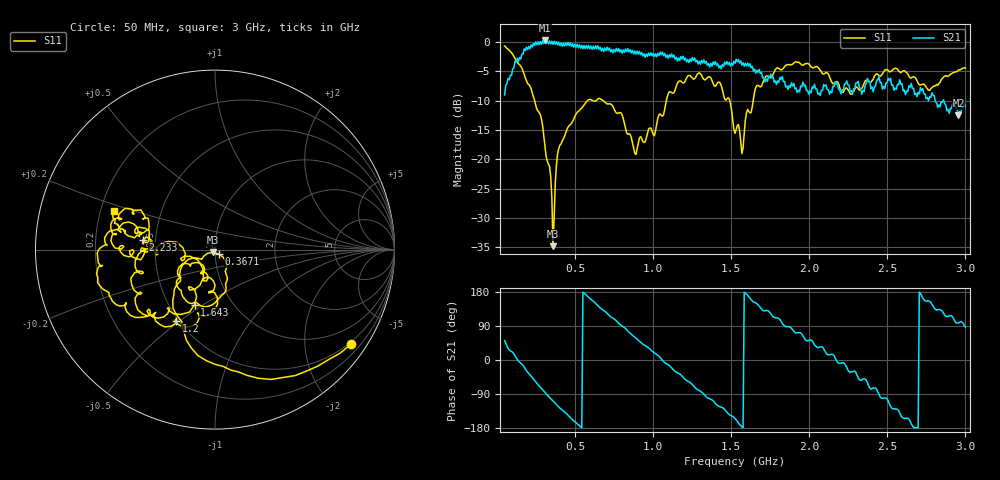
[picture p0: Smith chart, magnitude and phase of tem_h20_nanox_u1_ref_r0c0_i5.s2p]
! nanovna_capture.py 2026-10-26T21:55:45+0900
! NanoVNA-F_V2 fw 0.6.0 SN 4A3639384505514B
! cal: load open short thru cal'ed  over 50000000-3000000000 Hz, 201 points
! points 401, avg 4
! TEM h=20, genuine Nano X, 0 deg, centred, interleaved run G5
# HZ S RI R 50
! S12 and S22 are not measured (written as 0)
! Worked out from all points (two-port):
!   401 points, 50 MHz to 3 GHz, reference 50 ohm
!   highest |S21| = 0.26 dB at 308.1 MHz (marker M1); lowest = -12.5 dB at 2.956 GHz (marker M2)
!   |S21| within 3 dB of the highest: 154.8 MHz to 1.097 GHz (942 MHz wide, 151 % of centre); 1.098 GHz to 1.139 GHz (41.74 MHz wide, 3.73 % of centre) (the widest 2 of 9)
!   lowest |S11| = -34.8 dB at 359.8 MHz (marker M3), VSWR 1.04, Z = 49 - j1.53 ohm
!   |S11| at or under -10 dB: 242.3 MHz to 581 MHz (338.6 MHz wide, 82.3 % of centre); 680.6 MHz to 1.086 GHz (405 MHz wide, 45.9 % of centre); 1.491 GHz to 1.641 GHz (150.4 MHz wide, 9.6 % of centre) (the widest 3 of 4)
!   S12 and S22 are empty: the file has one direction only
!   S11 on the Smith chart (normalised r, x): 50 MHz: 0.44, -3.14; 367.1 MHz: 1.04, -0.05; 1.2 GHz: 0.49, -0.48; 1.643 GHz: 0.67, -0.46; 2.233 GHz: 0.43, +0.05; 3 GHz: 0.26, +0.17
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5e7  0.7583 -0.5264  0.2227 0.274  0 0  0 0
1.75375e8  -0.1592 -0.5049  0.827 -0.2818  0 0  0 0
3.08125e8  -0.1207 -0.0462  0.0813 -1.027  0 0  0 0
3.5975e8  -0.00937 -0.0155  -0.3006 -0.9073  0 0  0 0
3.67125e8  0.0216 -0.0241  -0.3665 -0.9463  0 0  0 0
4.04e8  0.058 -0.1183  -0.5601 -0.7437  0 0  0 0
5.44125e8  0.0193 -0.2725  -0.9364 -0.0203  0 0  0 0
7.80125e8  -0.1937 -0.1562  -0.1066 0.8707  0 0  0 0
8.83375e8  -0.0818 -0.0769  0.4133 0.7285  0 0  0 0
1.03825e9  -0.02 -0.2379  0.7535 0.1333  0 0  0 0
1.2005e9  -0.2145 -0.3955  0.4585 -0.5298  0 0  0 0
1.429125e9  -0.4445 -0.0614  -0.3425 -0.5252  0 0  0 0
1.525e9  -0.1647 -0.0248  -0.5943 -0.2847  0 0  0 0
1.56925e9  -0.0951 -0.0584  -0.6343 -0.037  0 0  0 0
1.643e9  -0.1141 -0.3065  -0.5025 0.2558  0 0  0 0
1.827375e9  -0.4967 -0.3063  -0.0603 0.5041  0 0  0 0
2.019125e9  -0.6038 0.0274  0.264 0.3188  0 0  0 0
2.233e9  -0.4011 0.0536  0.4271 -0.1084  0 0  0 0
2.51325e9  -0.5494 0.0889  -0.2079 -0.4224  0 0  0 0
2.653375e9  -0.4509 0.2002  -0.4341 -0.091  0 0  0 0
2.95575e9  -0.5596 0.1463  -0.0304 0.2346  0 0  0 0
3e9  -0.5603 0.2126  0.0147 0.282  0 0  0 0
